VERSION 5.8 ;
DIVIDERCHAR "/" ;
BUSBITCHARS "[]" ;

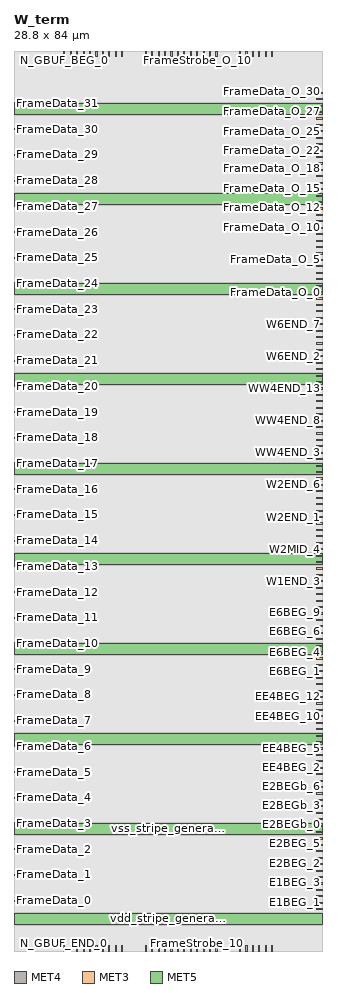
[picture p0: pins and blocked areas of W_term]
MACRO W_term
  CLASS BLOCK ;
  FOREIGN W_term ;
  ORIGIN 0.0 0.0 ;
  SIZE 28.800 BY 84.000 ;
  SYMMETRY X Y ;
  PIN S_GBUF_FEED_END_0
    DIRECTION INPUT ;
    USE SIGNAL ;
    PORT
      LAYER MET4 ;
        RECT 7.050 83.450 7.150 84.000 ;
    END
  END S_GBUF_FEED_END_0
  PIN S_GBUF_FEED_END_1
    DIRECTION INPUT ;
    USE SIGNAL ;
    PORT
      LAYER MET4 ;
        RECT 7.650 83.450 7.750 84.000 ;
    END
  END S_GBUF_FEED_END_1
  PIN S_GBUF_FEED_END_2
    DIRECTION INPUT ;
    USE SIGNAL ;
    PORT
      LAYER MET4 ;
        RECT 8.250 83.450 8.350 84.000 ;
    END
  END S_GBUF_FEED_END_2
  PIN S_GBUF_FEED_END_3
    DIRECTION INPUT ;
    USE SIGNAL ;
    PORT
      LAYER MET4 ;
        RECT 8.850 83.450 8.950 84.000 ;
    END
  END S_GBUF_FEED_END_3
  PIN N_GBUF_BEG_0
    DIRECTION OUTPUT ;
    USE SIGNAL ;
    PORT
      LAYER MET4 ;
        RECT 4.650 83.450 4.750 84.000 ;
    END
  END N_GBUF_BEG_0
  PIN N_GBUF_BEG_1
    DIRECTION OUTPUT ;
    USE SIGNAL ;
    PORT
      LAYER MET4 ;
        RECT 5.250 83.450 5.350 84.000 ;
    END
  END N_GBUF_BEG_1
  PIN N_GBUF_BEG_2
    DIRECTION OUTPUT ;
    USE SIGNAL ;
    PORT
      LAYER MET4 ;
        RECT 5.850 83.450 5.950 84.000 ;
    END
  END N_GBUF_BEG_2
  PIN N_GBUF_BEG_3
    DIRECTION OUTPUT ;
    USE SIGNAL ;
    PORT
      LAYER MET4 ;
        RECT 6.450 83.450 6.550 84.000 ;
    END
  END N_GBUF_BEG_3
  PIN E1BEG_0
    DIRECTION OUTPUT ;
    USE SIGNAL ;
    PORT
      LAYER MET3 ;
        RECT 28.250 3.850 28.800 3.950 ;
    END
  END E1BEG_0
  PIN E1BEG_1
    DIRECTION OUTPUT ;
    USE SIGNAL ;
    PORT
      LAYER MET3 ;
        RECT 28.250 4.450 28.800 4.550 ;
    END
  END E1BEG_1
  PIN E1BEG_2
    DIRECTION OUTPUT ;
    USE SIGNAL ;
    PORT
      LAYER MET3 ;
        RECT 28.250 5.050 28.800 5.150 ;
    END
  END E1BEG_2
  PIN E1BEG_3
    DIRECTION OUTPUT ;
    USE SIGNAL ;
    PORT
      LAYER MET3 ;
        RECT 28.250 5.650 28.800 5.750 ;
    END
  END E1BEG_3
  PIN E2BEG_0
    DIRECTION OUTPUT ;
    USE SIGNAL ;
    PORT
      LAYER MET3 ;
        RECT 28.250 6.250 28.800 6.350 ;
    END
  END E2BEG_0
  PIN E2BEG_1
    DIRECTION OUTPUT ;
    USE SIGNAL ;
    PORT
      LAYER MET3 ;
        RECT 28.250 6.850 28.800 6.950 ;
    END
  END E2BEG_1
  PIN E2BEG_2
    DIRECTION OUTPUT ;
    USE SIGNAL ;
    PORT
      LAYER MET3 ;
        RECT 28.250 7.450 28.800 7.550 ;
    END
  END E2BEG_2
  PIN E2BEG_3
    DIRECTION OUTPUT ;
    USE SIGNAL ;
    PORT
      LAYER MET3 ;
        RECT 28.250 8.050 28.800 8.150 ;
    END
  END E2BEG_3
  PIN E2BEG_4
    DIRECTION OUTPUT ;
    USE SIGNAL ;
    PORT
      LAYER MET3 ;
        RECT 28.250 8.650 28.800 8.750 ;
    END
  END E2BEG_4
  PIN E2BEG_5
    DIRECTION OUTPUT ;
    USE SIGNAL ;
    PORT
      LAYER MET3 ;
        RECT 28.250 9.250 28.800 9.350 ;
    END
  END E2BEG_5
  PIN E2BEG_6
    DIRECTION OUTPUT ;
    USE SIGNAL ;
    PORT
      LAYER MET3 ;
        RECT 28.250 9.850 28.800 9.950 ;
    END
  END E2BEG_6
  PIN E2BEG_7
    DIRECTION OUTPUT ;
    USE SIGNAL ;
    PORT
      LAYER MET3 ;
        RECT 28.250 10.450 28.800 10.550 ;
    END
  END E2BEG_7
  PIN E2BEGb_0
    DIRECTION OUTPUT ;
    USE SIGNAL ;
    PORT
      LAYER MET3 ;
        RECT 28.250 11.050 28.800 11.150 ;
    END
  END E2BEGb_0
  PIN E2BEGb_1
    DIRECTION OUTPUT ;
    USE SIGNAL ;
    PORT
      LAYER MET3 ;
        RECT 28.250 11.650 28.800 11.750 ;
    END
  END E2BEGb_1
  PIN E2BEGb_2
    DIRECTION OUTPUT ;
    USE SIGNAL ;
    PORT
      LAYER MET3 ;
        RECT 28.250 12.250 28.800 12.350 ;
    END
  END E2BEGb_2
  PIN E2BEGb_3
    DIRECTION OUTPUT ;
    USE SIGNAL ;
    PORT
      LAYER MET3 ;
        RECT 28.250 12.850 28.800 12.950 ;
    END
  END E2BEGb_3
  PIN E2BEGb_4
    DIRECTION OUTPUT ;
    USE SIGNAL ;
    PORT
      LAYER MET3 ;
        RECT 28.250 13.450 28.800 13.550 ;
    END
  END E2BEGb_4
  PIN E2BEGb_5
    DIRECTION OUTPUT ;
    USE SIGNAL ;
    PORT
      LAYER MET3 ;
        RECT 28.250 14.050 28.800 14.150 ;
    END
  END E2BEGb_5
  PIN E2BEGb_6
    DIRECTION OUTPUT ;
    USE SIGNAL ;
    PORT
      LAYER MET3 ;
        RECT 28.250 14.650 28.800 14.750 ;
    END
  END E2BEGb_6
  PIN E2BEGb_7
    DIRECTION OUTPUT ;
    USE SIGNAL ;
    PORT
      LAYER MET3 ;
        RECT 28.250 15.250 28.800 15.350 ;
    END
  END E2BEGb_7
  PIN EE4BEG_0
    DIRECTION OUTPUT ;
    USE SIGNAL ;
    PORT
      LAYER MET3 ;
        RECT 28.250 15.850 28.800 15.950 ;
    END
  END EE4BEG_0
  PIN EE4BEG_1
    DIRECTION OUTPUT ;
    USE SIGNAL ;
    PORT
      LAYER MET3 ;
        RECT 28.250 16.450 28.800 16.550 ;
    END
  END EE4BEG_1
  PIN EE4BEG_2
    DIRECTION OUTPUT ;
    USE SIGNAL ;
    PORT
      LAYER MET3 ;
        RECT 28.250 17.050 28.800 17.150 ;
    END
  END EE4BEG_2
  PIN EE4BEG_3
    DIRECTION OUTPUT ;
    USE SIGNAL ;
    PORT
      LAYER MET3 ;
        RECT 28.250 17.650 28.800 17.750 ;
    END
  END EE4BEG_3
  PIN EE4BEG_4
    DIRECTION OUTPUT ;
    USE SIGNAL ;
    PORT
      LAYER MET3 ;
        RECT 28.250 18.250 28.800 18.350 ;
    END
  END EE4BEG_4
  PIN EE4BEG_5
    DIRECTION OUTPUT ;
    USE SIGNAL ;
    PORT
      LAYER MET3 ;
        RECT 28.250 18.850 28.800 18.950 ;
    END
  END EE4BEG_5
  PIN EE4BEG_6
    DIRECTION OUTPUT ;
    USE SIGNAL ;
    PORT
      LAYER MET3 ;
        RECT 28.250 19.450 28.800 19.550 ;
    END
  END EE4BEG_6
  PIN EE4BEG_7
    DIRECTION OUTPUT ;
    USE SIGNAL ;
    PORT
      LAYER MET3 ;
        RECT 28.250 20.050 28.800 20.150 ;
    END
  END EE4BEG_7
  PIN EE4BEG_8
    DIRECTION OUTPUT ;
    USE SIGNAL ;
    PORT
      LAYER MET3 ;
        RECT 28.250 20.650 28.800 20.750 ;
    END
  END EE4BEG_8
  PIN EE4BEG_9
    DIRECTION OUTPUT ;
    USE SIGNAL ;
    PORT
      LAYER MET3 ;
        RECT 28.250 21.250 28.800 21.350 ;
    END
  END EE4BEG_9
  PIN EE4BEG_10
    DIRECTION OUTPUT ;
    USE SIGNAL ;
    PORT
      LAYER MET3 ;
        RECT 28.250 21.850 28.800 21.950 ;
    END
  END EE4BEG_10
  PIN EE4BEG_11
    DIRECTION OUTPUT ;
    USE SIGNAL ;
    PORT
      LAYER MET3 ;
        RECT 28.250 22.450 28.800 22.550 ;
    END
  END EE4BEG_11
  PIN EE4BEG_12
    DIRECTION OUTPUT ;
    USE SIGNAL ;
    PORT
      LAYER MET3 ;
        RECT 28.250 23.050 28.800 23.150 ;
    END
  END EE4BEG_12
  PIN EE4BEG_13
    DIRECTION OUTPUT ;
    USE SIGNAL ;
    PORT
      LAYER MET3 ;
        RECT 28.250 23.650 28.800 23.750 ;
    END
  END EE4BEG_13
  PIN EE4BEG_14
    DIRECTION OUTPUT ;
    USE SIGNAL ;
    PORT
      LAYER MET3 ;
        RECT 28.250 24.250 28.800 24.350 ;
    END
  END EE4BEG_14
  PIN EE4BEG_15
    DIRECTION OUTPUT ;
    USE SIGNAL ;
    PORT
      LAYER MET3 ;
        RECT 28.250 24.850 28.800 24.950 ;
    END
  END EE4BEG_15
  PIN E6BEG_0
    DIRECTION OUTPUT ;
    USE SIGNAL ;
    PORT
      LAYER MET3 ;
        RECT 28.250 25.450 28.800 25.550 ;
    END
  END E6BEG_0
  PIN E6BEG_1
    DIRECTION OUTPUT ;
    USE SIGNAL ;
    PORT
      LAYER MET3 ;
        RECT 28.250 26.050 28.800 26.150 ;
    END
  END E6BEG_1
  PIN E6BEG_2
    DIRECTION OUTPUT ;
    USE SIGNAL ;
    PORT
      LAYER MET3 ;
        RECT 28.250 26.650 28.800 26.750 ;
    END
  END E6BEG_2
  PIN E6BEG_3
    DIRECTION OUTPUT ;
    USE SIGNAL ;
    PORT
      LAYER MET3 ;
        RECT 28.250 27.250 28.800 27.350 ;
    END
  END E6BEG_3
  PIN E6BEG_4
    DIRECTION OUTPUT ;
    USE SIGNAL ;
    PORT
      LAYER MET3 ;
        RECT 28.250 27.850 28.800 27.950 ;
    END
  END E6BEG_4
  PIN E6BEG_5
    DIRECTION OUTPUT ;
    USE SIGNAL ;
    PORT
      LAYER MET3 ;
        RECT 28.250 28.450 28.800 28.550 ;
    END
  END E6BEG_5
  PIN E6BEG_6
    DIRECTION OUTPUT ;
    USE SIGNAL ;
    PORT
      LAYER MET3 ;
        RECT 28.250 29.050 28.800 29.150 ;
    END
  END E6BEG_6
  PIN E6BEG_7
    DIRECTION OUTPUT ;
    USE SIGNAL ;
    PORT
      LAYER MET3 ;
        RECT 28.250 29.650 28.800 29.750 ;
    END
  END E6BEG_7
  PIN E6BEG_8
    DIRECTION OUTPUT ;
    USE SIGNAL ;
    PORT
      LAYER MET3 ;
        RECT 28.250 30.250 28.800 30.350 ;
    END
  END E6BEG_8
  PIN E6BEG_9
    DIRECTION OUTPUT ;
    USE SIGNAL ;
    PORT
      LAYER MET3 ;
        RECT 28.250 30.850 28.800 30.950 ;
    END
  END E6BEG_9
  PIN E6BEG_10
    DIRECTION OUTPUT ;
    USE SIGNAL ;
    PORT
      LAYER MET3 ;
        RECT 28.250 31.450 28.800 31.550 ;
    END
  END E6BEG_10
  PIN E6BEG_11
    DIRECTION OUTPUT ;
    USE SIGNAL ;
    PORT
      LAYER MET3 ;
        RECT 28.250 32.050 28.800 32.150 ;
    END
  END E6BEG_11
  PIN W1END_0
    DIRECTION INPUT ;
    USE SIGNAL ;
    PORT
      LAYER MET3 ;
        RECT 28.250 32.650 28.800 32.750 ;
    END
  END W1END_0
  PIN W1END_1
    DIRECTION INPUT ;
    USE SIGNAL ;
    PORT
      LAYER MET3 ;
        RECT 28.250 33.250 28.800 33.350 ;
    END
  END W1END_1
  PIN W1END_2
    DIRECTION INPUT ;
    USE SIGNAL ;
    PORT
      LAYER MET3 ;
        RECT 28.250 33.850 28.800 33.950 ;
    END
  END W1END_2
  PIN W1END_3
    DIRECTION INPUT ;
    USE SIGNAL ;
    PORT
      LAYER MET3 ;
        RECT 28.250 34.450 28.800 34.550 ;
    END
  END W1END_3
  PIN W2MID_0
    DIRECTION INPUT ;
    USE SIGNAL ;
    PORT
      LAYER MET3 ;
        RECT 28.250 35.050 28.800 35.150 ;
    END
  END W2MID_0
  PIN W2MID_1
    DIRECTION INPUT ;
    USE SIGNAL ;
    PORT
      LAYER MET3 ;
        RECT 28.250 35.650 28.800 35.750 ;
    END
  END W2MID_1
  PIN W2MID_2
    DIRECTION INPUT ;
    USE SIGNAL ;
    PORT
      LAYER MET3 ;
        RECT 28.250 36.250 28.800 36.350 ;
    END
  END W2MID_2
  PIN W2MID_3
    DIRECTION INPUT ;
    USE SIGNAL ;
    PORT
      LAYER MET3 ;
        RECT 28.250 36.850 28.800 36.950 ;
    END
  END W2MID_3
  PIN W2MID_4
    DIRECTION INPUT ;
    USE SIGNAL ;
    PORT
      LAYER MET3 ;
        RECT 28.250 37.450 28.800 37.550 ;
    END
  END W2MID_4
  PIN W2MID_5
    DIRECTION INPUT ;
    USE SIGNAL ;
    PORT
      LAYER MET3 ;
        RECT 28.250 38.050 28.800 38.150 ;
    END
  END W2MID_5
  PIN W2MID_6
    DIRECTION INPUT ;
    USE SIGNAL ;
    PORT
      LAYER MET3 ;
        RECT 28.250 38.650 28.800 38.750 ;
    END
  END W2MID_6
  PIN W2MID_7
    DIRECTION INPUT ;
    USE SIGNAL ;
    PORT
      LAYER MET3 ;
        RECT 28.250 39.250 28.800 39.350 ;
    END
  END W2MID_7
  PIN W2END_0
    DIRECTION INPUT ;
    USE SIGNAL ;
    PORT
      LAYER MET3 ;
        RECT 28.250 39.850 28.800 39.950 ;
    END
  END W2END_0
  PIN W2END_1
    DIRECTION INPUT ;
    USE SIGNAL ;
    PORT
      LAYER MET3 ;
        RECT 28.250 40.450 28.800 40.550 ;
    END
  END W2END_1
  PIN W2END_2
    DIRECTION INPUT ;
    USE SIGNAL ;
    PORT
      LAYER MET3 ;
        RECT 28.250 41.050 28.800 41.150 ;
    END
  END W2END_2
  PIN W2END_3
    DIRECTION INPUT ;
    USE SIGNAL ;
    PORT
      LAYER MET3 ;
        RECT 28.250 41.650 28.800 41.750 ;
    END
  END W2END_3
  PIN W2END_4
    DIRECTION INPUT ;
    USE SIGNAL ;
    PORT
      LAYER MET3 ;
        RECT 28.250 42.250 28.800 42.350 ;
    END
  END W2END_4
  PIN W2END_5
    DIRECTION INPUT ;
    USE SIGNAL ;
    PORT
      LAYER MET3 ;
        RECT 28.250 42.850 28.800 42.950 ;
    END
  END W2END_5
  PIN W2END_6
    DIRECTION INPUT ;
    USE SIGNAL ;
    PORT
      LAYER MET3 ;
        RECT 28.250 43.450 28.800 43.550 ;
    END
  END W2END_6
  PIN W2END_7
    DIRECTION INPUT ;
    USE SIGNAL ;
    PORT
      LAYER MET3 ;
        RECT 28.250 44.050 28.800 44.150 ;
    END
  END W2END_7
  PIN WW4END_0
    DIRECTION INPUT ;
    USE SIGNAL ;
    PORT
      LAYER MET3 ;
        RECT 28.250 44.650 28.800 44.750 ;
    END
  END WW4END_0
  PIN WW4END_1
    DIRECTION INPUT ;
    USE SIGNAL ;
    PORT
      LAYER MET3 ;
        RECT 28.250 45.250 28.800 45.350 ;
    END
  END WW4END_1
  PIN WW4END_2
    DIRECTION INPUT ;
    USE SIGNAL ;
    PORT
      LAYER MET3 ;
        RECT 28.250 45.850 28.800 45.950 ;
    END
  END WW4END_2
  PIN WW4END_3
    DIRECTION INPUT ;
    USE SIGNAL ;
    PORT
      LAYER MET3 ;
        RECT 28.250 46.450 28.800 46.550 ;
    END
  END WW4END_3
  PIN WW4END_4
    DIRECTION INPUT ;
    USE SIGNAL ;
    PORT
      LAYER MET3 ;
        RECT 28.250 47.050 28.800 47.150 ;
    END
  END WW4END_4
  PIN WW4END_5
    DIRECTION INPUT ;
    USE SIGNAL ;
    PORT
      LAYER MET3 ;
        RECT 28.250 47.650 28.800 47.750 ;
    END
  END WW4END_5
  PIN WW4END_6
    DIRECTION INPUT ;
    USE SIGNAL ;
    PORT
      LAYER MET3 ;
        RECT 28.250 48.250 28.800 48.350 ;
    END
  END WW4END_6
  PIN WW4END_7
    DIRECTION INPUT ;
    USE SIGNAL ;
    PORT
      LAYER MET3 ;
        RECT 28.250 48.850 28.800 48.950 ;
    END
  END WW4END_7
  PIN WW4END_8
    DIRECTION INPUT ;
    USE SIGNAL ;
    PORT
      LAYER MET3 ;
        RECT 28.250 49.450 28.800 49.550 ;
    END
  END WW4END_8
  PIN WW4END_9
    DIRECTION INPUT ;
    USE SIGNAL ;
    PORT
      LAYER MET3 ;
        RECT 28.250 50.050 28.800 50.150 ;
    END
  END WW4END_9
  PIN WW4END_10
    DIRECTION INPUT ;
    USE SIGNAL ;
    PORT
      LAYER MET3 ;
        RECT 28.250 50.650 28.800 50.750 ;
    END
  END WW4END_10
  PIN WW4END_11
    DIRECTION INPUT ;
    USE SIGNAL ;
    PORT
      LAYER MET3 ;
        RECT 28.250 51.250 28.800 51.350 ;
    END
  END WW4END_11
  PIN WW4END_12
    DIRECTION INPUT ;
    USE SIGNAL ;
    PORT
      LAYER MET3 ;
        RECT 28.250 51.850 28.800 51.950 ;
    END
  END WW4END_12
  PIN WW4END_13
    DIRECTION INPUT ;
    USE SIGNAL ;
    PORT
      LAYER MET3 ;
        RECT 28.250 52.450 28.800 52.550 ;
    END
  END WW4END_13
  PIN WW4END_14
    DIRECTION INPUT ;
    USE SIGNAL ;
    PORT
      LAYER MET3 ;
        RECT 28.250 53.050 28.800 53.150 ;
    END
  END WW4END_14
  PIN WW4END_15
    DIRECTION INPUT ;
    USE SIGNAL ;
    PORT
      LAYER MET3 ;
        RECT 28.250 53.650 28.800 53.750 ;
    END
  END WW4END_15
  PIN W6END_0
    DIRECTION INPUT ;
    USE SIGNAL ;
    PORT
      LAYER MET3 ;
        RECT 28.250 54.250 28.800 54.350 ;
    END
  END W6END_0
  PIN W6END_1
    DIRECTION INPUT ;
    USE SIGNAL ;
    PORT
      LAYER MET3 ;
        RECT 28.250 54.850 28.800 54.950 ;
    END
  END W6END_1
  PIN W6END_2
    DIRECTION INPUT ;
    USE SIGNAL ;
    PORT
      LAYER MET3 ;
        RECT 28.250 55.450 28.800 55.550 ;
    END
  END W6END_2
  PIN W6END_3
    DIRECTION INPUT ;
    USE SIGNAL ;
    PORT
      LAYER MET3 ;
        RECT 28.250 56.050 28.800 56.150 ;
    END
  END W6END_3
  PIN W6END_4
    DIRECTION INPUT ;
    USE SIGNAL ;
    PORT
      LAYER MET3 ;
        RECT 28.250 56.650 28.800 56.750 ;
    END
  END W6END_4
  PIN W6END_5
    DIRECTION INPUT ;
    USE SIGNAL ;
    PORT
      LAYER MET3 ;
        RECT 28.250 57.250 28.800 57.350 ;
    END
  END W6END_5
  PIN W6END_6
    DIRECTION INPUT ;
    USE SIGNAL ;
    PORT
      LAYER MET3 ;
        RECT 28.250 57.850 28.800 57.950 ;
    END
  END W6END_6
  PIN W6END_7
    DIRECTION INPUT ;
    USE SIGNAL ;
    PORT
      LAYER MET3 ;
        RECT 28.250 58.450 28.800 58.550 ;
    END
  END W6END_7
  PIN W6END_8
    DIRECTION INPUT ;
    USE SIGNAL ;
    PORT
      LAYER MET3 ;
        RECT 28.250 59.050 28.800 59.150 ;
    END
  END W6END_8
  PIN W6END_9
    DIRECTION INPUT ;
    USE SIGNAL ;
    PORT
      LAYER MET3 ;
        RECT 28.250 59.650 28.800 59.750 ;
    END
  END W6END_9
  PIN W6END_10
    DIRECTION INPUT ;
    USE SIGNAL ;
    PORT
      LAYER MET3 ;
        RECT 28.250 60.250 28.800 60.350 ;
    END
  END W6END_10
  PIN W6END_11
    DIRECTION INPUT ;
    USE SIGNAL ;
    PORT
      LAYER MET3 ;
        RECT 28.250 60.850 28.800 60.950 ;
    END
  END W6END_11
  PIN S_GBUF_FEED_BEG_0
    DIRECTION OUTPUT ;
    USE SIGNAL ;
    PORT
      LAYER MET4 ;
        RECT 7.050 0.000 7.150 0.550 ;
    END
  END S_GBUF_FEED_BEG_0
  PIN S_GBUF_FEED_BEG_1
    DIRECTION OUTPUT ;
    USE SIGNAL ;
    PORT
      LAYER MET4 ;
        RECT 7.650 0.000 7.750 0.550 ;
    END
  END S_GBUF_FEED_BEG_1
  PIN S_GBUF_FEED_BEG_2
    DIRECTION OUTPUT ;
    USE SIGNAL ;
    PORT
      LAYER MET4 ;
        RECT 8.250 0.000 8.350 0.550 ;
    END
  END S_GBUF_FEED_BEG_2
  PIN S_GBUF_FEED_BEG_3
    DIRECTION OUTPUT ;
    USE SIGNAL ;
    PORT
      LAYER MET4 ;
        RECT 8.850 0.000 8.950 0.550 ;
    END
  END S_GBUF_FEED_BEG_3
  PIN N_GBUF_END_0
    DIRECTION INPUT ;
    USE SIGNAL ;
    PORT
      LAYER MET4 ;
        RECT 4.650 0.000 4.750 0.550 ;
    END
  END N_GBUF_END_0
  PIN N_GBUF_END_1
    DIRECTION INPUT ;
    USE SIGNAL ;
    PORT
      LAYER MET4 ;
        RECT 5.250 0.000 5.350 0.550 ;
    END
  END N_GBUF_END_1
  PIN N_GBUF_END_2
    DIRECTION INPUT ;
    USE SIGNAL ;
    PORT
      LAYER MET4 ;
        RECT 5.850 0.000 5.950 0.550 ;
    END
  END N_GBUF_END_2
  PIN N_GBUF_END_3
    DIRECTION INPUT ;
    USE SIGNAL ;
    PORT
      LAYER MET4 ;
        RECT 6.450 0.000 6.550 0.550 ;
    END
  END N_GBUF_END_3
  PIN FrameData_0
    DIRECTION INPUT ;
    USE SIGNAL ;
    PORT
      LAYER MET3 ;
        RECT 0.000 4.650 0.550 4.750 ;
    END
  END FrameData_0
  PIN FrameData_1
    DIRECTION INPUT ;
    USE SIGNAL ;
    PORT
      LAYER MET3 ;
        RECT 0.000 7.050 0.550 7.150 ;
    END
  END FrameData_1
  PIN FrameData_2
    DIRECTION INPUT ;
    USE SIGNAL ;
    PORT
      LAYER MET3 ;
        RECT 0.000 9.450 0.550 9.550 ;
    END
  END FrameData_2
  PIN FrameData_3
    DIRECTION INPUT ;
    USE SIGNAL ;
    PORT
      LAYER MET3 ;
        RECT 0.000 11.850 0.550 11.950 ;
    END
  END FrameData_3
  PIN FrameData_4
    DIRECTION INPUT ;
    USE SIGNAL ;
    PORT
      LAYER MET3 ;
        RECT 0.000 14.250 0.550 14.350 ;
    END
  END FrameData_4
  PIN FrameData_5
    DIRECTION INPUT ;
    USE SIGNAL ;
    PORT
      LAYER MET3 ;
        RECT 0.000 16.650 0.550 16.750 ;
    END
  END FrameData_5
  PIN FrameData_6
    DIRECTION INPUT ;
    USE SIGNAL ;
    PORT
      LAYER MET3 ;
        RECT 0.000 19.050 0.550 19.150 ;
    END
  END FrameData_6
  PIN FrameData_7
    DIRECTION INPUT ;
    USE SIGNAL ;
    PORT
      LAYER MET3 ;
        RECT 0.000 21.450 0.550 21.550 ;
    END
  END FrameData_7
  PIN FrameData_8
    DIRECTION INPUT ;
    USE SIGNAL ;
    PORT
      LAYER MET3 ;
        RECT 0.000 23.850 0.550 23.950 ;
    END
  END FrameData_8
  PIN FrameData_9
    DIRECTION INPUT ;
    USE SIGNAL ;
    PORT
      LAYER MET3 ;
        RECT 0.000 26.250 0.550 26.350 ;
    END
  END FrameData_9
  PIN FrameData_10
    DIRECTION INPUT ;
    USE SIGNAL ;
    PORT
      LAYER MET3 ;
        RECT 0.000 28.650 0.550 28.750 ;
    END
  END FrameData_10
  PIN FrameData_11
    DIRECTION INPUT ;
    USE SIGNAL ;
    PORT
      LAYER MET3 ;
        RECT 0.000 31.050 0.550 31.150 ;
    END
  END FrameData_11
  PIN FrameData_12
    DIRECTION INPUT ;
    USE SIGNAL ;
    PORT
      LAYER MET3 ;
        RECT 0.000 33.450 0.550 33.550 ;
    END
  END FrameData_12
  PIN FrameData_13
    DIRECTION INPUT ;
    USE SIGNAL ;
    PORT
      LAYER MET3 ;
        RECT 0.000 35.850 0.550 35.950 ;
    END
  END FrameData_13
  PIN FrameData_14
    DIRECTION INPUT ;
    USE SIGNAL ;
    PORT
      LAYER MET3 ;
        RECT 0.000 38.250 0.550 38.350 ;
    END
  END FrameData_14
  PIN FrameData_15
    DIRECTION INPUT ;
    USE SIGNAL ;
    PORT
      LAYER MET3 ;
        RECT 0.000 40.650 0.550 40.750 ;
    END
  END FrameData_15
  PIN FrameData_16
    DIRECTION INPUT ;
    USE SIGNAL ;
    PORT
      LAYER MET3 ;
        RECT 0.000 43.050 0.550 43.150 ;
    END
  END FrameData_16
  PIN FrameData_17
    DIRECTION INPUT ;
    USE SIGNAL ;
    PORT
      LAYER MET3 ;
        RECT 0.000 45.450 0.550 45.550 ;
    END
  END FrameData_17
  PIN FrameData_18
    DIRECTION INPUT ;
    USE SIGNAL ;
    PORT
      LAYER MET3 ;
        RECT 0.000 47.850 0.550 47.950 ;
    END
  END FrameData_18
  PIN FrameData_19
    DIRECTION INPUT ;
    USE SIGNAL ;
    PORT
      LAYER MET3 ;
        RECT 0.000 50.250 0.550 50.350 ;
    END
  END FrameData_19
  PIN FrameData_20
    DIRECTION INPUT ;
    USE SIGNAL ;
    PORT
      LAYER MET3 ;
        RECT 0.000 52.650 0.550 52.750 ;
    END
  END FrameData_20
  PIN FrameData_21
    DIRECTION INPUT ;
    USE SIGNAL ;
    PORT
      LAYER MET3 ;
        RECT 0.000 55.050 0.550 55.150 ;
    END
  END FrameData_21
  PIN FrameData_22
    DIRECTION INPUT ;
    USE SIGNAL ;
    PORT
      LAYER MET3 ;
        RECT 0.000 57.450 0.550 57.550 ;
    END
  END FrameData_22
  PIN FrameData_23
    DIRECTION INPUT ;
    USE SIGNAL ;
    PORT
      LAYER MET3 ;
        RECT 0.000 59.850 0.550 59.950 ;
    END
  END FrameData_23
  PIN FrameData_24
    DIRECTION INPUT ;
    USE SIGNAL ;
    PORT
      LAYER MET3 ;
        RECT 0.000 62.250 0.550 62.350 ;
    END
  END FrameData_24
  PIN FrameData_25
    DIRECTION INPUT ;
    USE SIGNAL ;
    PORT
      LAYER MET3 ;
        RECT 0.000 64.650 0.550 64.750 ;
    END
  END FrameData_25
  PIN FrameData_26
    DIRECTION INPUT ;
    USE SIGNAL ;
    PORT
      LAYER MET3 ;
        RECT 0.000 67.050 0.550 67.150 ;
    END
  END FrameData_26
  PIN FrameData_27
    DIRECTION INPUT ;
    USE SIGNAL ;
    PORT
      LAYER MET3 ;
        RECT 0.000 69.450 0.550 69.550 ;
    END
  END FrameData_27
  PIN FrameData_28
    DIRECTION INPUT ;
    USE SIGNAL ;
    PORT
      LAYER MET3 ;
        RECT 0.000 71.850 0.550 71.950 ;
    END
  END FrameData_28
  PIN FrameData_29
    DIRECTION INPUT ;
    USE SIGNAL ;
    PORT
      LAYER MET3 ;
        RECT 0.000 74.250 0.550 74.350 ;
    END
  END FrameData_29
  PIN FrameData_30
    DIRECTION INPUT ;
    USE SIGNAL ;
    PORT
      LAYER MET3 ;
        RECT 0.000 76.650 0.550 76.750 ;
    END
  END FrameData_30
  PIN FrameData_31
    DIRECTION INPUT ;
    USE SIGNAL ;
    PORT
      LAYER MET3 ;
        RECT 0.000 79.050 0.550 79.150 ;
    END
  END FrameData_31
  PIN FrameData_O_0
    DIRECTION OUTPUT ;
    USE SIGNAL ;
    PORT
      LAYER MET3 ;
        RECT 28.250 61.450 28.800 61.550 ;
    END
  END FrameData_O_0
  PIN FrameData_O_1
    DIRECTION OUTPUT ;
    USE SIGNAL ;
    PORT
      LAYER MET3 ;
        RECT 28.250 62.050 28.800 62.150 ;
    END
  END FrameData_O_1
  PIN FrameData_O_2
    DIRECTION OUTPUT ;
    USE SIGNAL ;
    PORT
      LAYER MET3 ;
        RECT 28.250 62.650 28.800 62.750 ;
    END
  END FrameData_O_2
  PIN FrameData_O_3
    DIRECTION OUTPUT ;
    USE SIGNAL ;
    PORT
      LAYER MET3 ;
        RECT 28.250 63.250 28.800 63.350 ;
    END
  END FrameData_O_3
  PIN FrameData_O_4
    DIRECTION OUTPUT ;
    USE SIGNAL ;
    PORT
      LAYER MET3 ;
        RECT 28.250 63.850 28.800 63.950 ;
    END
  END FrameData_O_4
  PIN FrameData_O_5
    DIRECTION OUTPUT ;
    USE SIGNAL ;
    PORT
      LAYER MET3 ;
        RECT 28.250 64.450 28.800 64.550 ;
    END
  END FrameData_O_5
  PIN FrameData_O_6
    DIRECTION OUTPUT ;
    USE SIGNAL ;
    PORT
      LAYER MET3 ;
        RECT 28.250 65.050 28.800 65.150 ;
    END
  END FrameData_O_6
  PIN FrameData_O_7
    DIRECTION OUTPUT ;
    USE SIGNAL ;
    PORT
      LAYER MET3 ;
        RECT 28.250 65.650 28.800 65.750 ;
    END
  END FrameData_O_7
  PIN FrameData_O_8
    DIRECTION OUTPUT ;
    USE SIGNAL ;
    PORT
      LAYER MET3 ;
        RECT 28.250 66.250 28.800 66.350 ;
    END
  END FrameData_O_8
  PIN FrameData_O_9
    DIRECTION OUTPUT ;
    USE SIGNAL ;
    PORT
      LAYER MET3 ;
        RECT 28.250 66.850 28.800 66.950 ;
    END
  END FrameData_O_9
  PIN FrameData_O_10
    DIRECTION OUTPUT ;
    USE SIGNAL ;
    PORT
      LAYER MET3 ;
        RECT 28.250 67.450 28.800 67.550 ;
    END
  END FrameData_O_10
  PIN FrameData_O_11
    DIRECTION OUTPUT ;
    USE SIGNAL ;
    PORT
      LAYER MET3 ;
        RECT 28.250 68.050 28.800 68.150 ;
    END
  END FrameData_O_11
  PIN FrameData_O_12
    DIRECTION OUTPUT ;
    USE SIGNAL ;
    PORT
      LAYER MET3 ;
        RECT 28.250 68.650 28.800 68.750 ;
    END
  END FrameData_O_12
  PIN FrameData_O_13
    DIRECTION OUTPUT ;
    USE SIGNAL ;
    PORT
      LAYER MET3 ;
        RECT 28.250 69.250 28.800 69.350 ;
    END
  END FrameData_O_13
  PIN FrameData_O_14
    DIRECTION OUTPUT ;
    USE SIGNAL ;
    PORT
      LAYER MET3 ;
        RECT 28.250 69.850 28.800 69.950 ;
    END
  END FrameData_O_14
  PIN FrameData_O_15
    DIRECTION OUTPUT ;
    USE SIGNAL ;
    PORT
      LAYER MET3 ;
        RECT 28.250 70.450 28.800 70.550 ;
    END
  END FrameData_O_15
  PIN FrameData_O_16
    DIRECTION OUTPUT ;
    USE SIGNAL ;
    PORT
      LAYER MET3 ;
        RECT 28.250 71.050 28.800 71.150 ;
    END
  END FrameData_O_16
  PIN FrameData_O_17
    DIRECTION OUTPUT ;
    USE SIGNAL ;
    PORT
      LAYER MET3 ;
        RECT 28.250 71.650 28.800 71.750 ;
    END
  END FrameData_O_17
  PIN FrameData_O_18
    DIRECTION OUTPUT ;
    USE SIGNAL ;
    PORT
      LAYER MET3 ;
        RECT 28.250 72.250 28.800 72.350 ;
    END
  END FrameData_O_18
  PIN FrameData_O_19
    DIRECTION OUTPUT ;
    USE SIGNAL ;
    PORT
      LAYER MET3 ;
        RECT 28.250 72.850 28.800 72.950 ;
    END
  END FrameData_O_19
  PIN FrameData_O_20
    DIRECTION OUTPUT ;
    USE SIGNAL ;
    PORT
      LAYER MET3 ;
        RECT 28.250 73.450 28.800 73.550 ;
    END
  END FrameData_O_20
  PIN FrameData_O_21
    DIRECTION OUTPUT ;
    USE SIGNAL ;
    PORT
      LAYER MET3 ;
        RECT 28.250 74.050 28.800 74.150 ;
    END
  END FrameData_O_21
  PIN FrameData_O_22
    DIRECTION OUTPUT ;
    USE SIGNAL ;
    PORT
      LAYER MET3 ;
        RECT 28.250 74.650 28.800 74.750 ;
    END
  END FrameData_O_22
  PIN FrameData_O_23
    DIRECTION OUTPUT ;
    USE SIGNAL ;
    PORT
      LAYER MET3 ;
        RECT 28.250 75.250 28.800 75.350 ;
    END
  END FrameData_O_23
  PIN FrameData_O_24
    DIRECTION OUTPUT ;
    USE SIGNAL ;
    PORT
      LAYER MET3 ;
        RECT 28.250 75.850 28.800 75.950 ;
    END
  END FrameData_O_24
  PIN FrameData_O_25
    DIRECTION OUTPUT ;
    USE SIGNAL ;
    PORT
      LAYER MET3 ;
        RECT 28.250 76.450 28.800 76.550 ;
    END
  END FrameData_O_25
  PIN FrameData_O_26
    DIRECTION OUTPUT ;
    USE SIGNAL ;
    PORT
      LAYER MET3 ;
        RECT 28.250 77.050 28.800 77.150 ;
    END
  END FrameData_O_26
  PIN FrameData_O_27
    DIRECTION OUTPUT ;
    USE SIGNAL ;
    PORT
      LAYER MET3 ;
        RECT 28.250 77.650 28.800 77.750 ;
    END
  END FrameData_O_27
  PIN FrameData_O_28
    DIRECTION OUTPUT ;
    USE SIGNAL ;
    PORT
      LAYER MET3 ;
        RECT 28.250 78.250 28.800 78.350 ;
    END
  END FrameData_O_28
  PIN FrameData_O_29
    DIRECTION OUTPUT ;
    USE SIGNAL ;
    PORT
      LAYER MET3 ;
        RECT 28.250 78.850 28.800 78.950 ;
    END
  END FrameData_O_29
  PIN FrameData_O_30
    DIRECTION OUTPUT ;
    USE SIGNAL ;
    PORT
      LAYER MET3 ;
        RECT 28.250 79.450 28.800 79.550 ;
    END
  END FrameData_O_30
  PIN FrameData_O_31
    DIRECTION OUTPUT ;
    USE SIGNAL ;
    PORT
      LAYER MET3 ;
        RECT 28.250 80.050 28.800 80.150 ;
    END
  END FrameData_O_31
  PIN FrameStrobe_0
    DIRECTION INPUT ;
    USE SIGNAL ;
    PORT
      LAYER MET4 ;
        RECT 9.450 0.000 9.550 0.550 ;
    END
  END FrameStrobe_0
  PIN FrameStrobe_1
    DIRECTION INPUT ;
    USE SIGNAL ;
    PORT
      LAYER MET4 ;
        RECT 10.050 0.000 10.150 0.550 ;
    END
  END FrameStrobe_1
  PIN FrameStrobe_2
    DIRECTION INPUT ;
    USE SIGNAL ;
    PORT
      LAYER MET4 ;
        RECT 12.250 0.000 12.350 0.550 ;
    END
  END FrameStrobe_2
  PIN FrameStrobe_3
    DIRECTION INPUT ;
    USE SIGNAL ;
    PORT
      LAYER MET4 ;
        RECT 12.850 0.000 12.950 0.550 ;
    END
  END FrameStrobe_3
  PIN FrameStrobe_4
    DIRECTION INPUT ;
    USE SIGNAL ;
    PORT
      LAYER MET4 ;
        RECT 13.450 0.000 13.550 0.550 ;
    END
  END FrameStrobe_4
  PIN FrameStrobe_5
    DIRECTION INPUT ;
    USE SIGNAL ;
    PORT
      LAYER MET4 ;
        RECT 14.050 0.000 14.150 0.550 ;
    END
  END FrameStrobe_5
  PIN FrameStrobe_6
    DIRECTION INPUT ;
    USE SIGNAL ;
    PORT
      LAYER MET4 ;
        RECT 14.650 0.000 14.750 0.550 ;
    END
  END FrameStrobe_6
  PIN FrameStrobe_7
    DIRECTION INPUT ;
    USE SIGNAL ;
    PORT
      LAYER MET4 ;
        RECT 15.250 0.000 15.350 0.550 ;
    END
  END FrameStrobe_7
  PIN FrameStrobe_8
    DIRECTION INPUT ;
    USE SIGNAL ;
    PORT
      LAYER MET4 ;
        RECT 15.850 0.000 15.950 0.550 ;
    END
  END FrameStrobe_8
  PIN FrameStrobe_9
    DIRECTION INPUT ;
    USE SIGNAL ;
    PORT
      LAYER MET4 ;
        RECT 16.450 0.000 16.550 0.550 ;
    END
  END FrameStrobe_9
  PIN FrameStrobe_10
    DIRECTION INPUT ;
    USE SIGNAL ;
    PORT
      LAYER MET4 ;
        RECT 17.050 0.000 17.150 0.550 ;
    END
  END FrameStrobe_10
  PIN FrameStrobe_11
    DIRECTION INPUT ;
    USE SIGNAL ;
    PORT
      LAYER MET4 ;
        RECT 17.650 0.000 17.750 0.550 ;
    END
  END FrameStrobe_11
  PIN FrameStrobe_12
    DIRECTION INPUT ;
    USE SIGNAL ;
    PORT
      LAYER MET4 ;
        RECT 18.250 0.000 18.350 0.550 ;
    END
  END FrameStrobe_12
  PIN FrameStrobe_13
    DIRECTION INPUT ;
    USE SIGNAL ;
    PORT
      LAYER MET4 ;
        RECT 18.850 0.000 18.950 0.550 ;
    END
  END FrameStrobe_13
  PIN FrameStrobe_14
    DIRECTION INPUT ;
    USE SIGNAL ;
    PORT
      LAYER MET4 ;
        RECT 21.050 0.000 21.150 0.550 ;
    END
  END FrameStrobe_14
  PIN FrameStrobe_15
    DIRECTION INPUT ;
    USE SIGNAL ;
    PORT
      LAYER MET4 ;
        RECT 21.650 0.000 21.750 0.550 ;
    END
  END FrameStrobe_15
  PIN FrameStrobe_16
    DIRECTION INPUT ;
    USE SIGNAL ;
    PORT
      LAYER MET4 ;
        RECT 22.250 0.000 22.350 0.550 ;
    END
  END FrameStrobe_16
  PIN FrameStrobe_17
    DIRECTION INPUT ;
    USE SIGNAL ;
    PORT
      LAYER MET4 ;
        RECT 22.850 0.000 22.950 0.550 ;
    END
  END FrameStrobe_17
  PIN FrameStrobe_18
    DIRECTION INPUT ;
    USE SIGNAL ;
    PORT
      LAYER MET4 ;
        RECT 23.450 0.000 23.550 0.550 ;
    END
  END FrameStrobe_18
  PIN FrameStrobe_19
    DIRECTION INPUT ;
    USE SIGNAL ;
    PORT
      LAYER MET4 ;
        RECT 24.050 0.000 24.150 0.550 ;
    END
  END FrameStrobe_19
  PIN FrameStrobe_O_0
    DIRECTION OUTPUT ;
    USE SIGNAL ;
    PORT
      LAYER MET4 ;
        RECT 9.450 83.450 9.550 84.000 ;
    END
  END FrameStrobe_O_0
  PIN FrameStrobe_O_1
    DIRECTION OUTPUT ;
    USE SIGNAL ;
    PORT
      LAYER MET4 ;
        RECT 10.050 83.450 10.150 84.000 ;
    END
  END FrameStrobe_O_1
  PIN FrameStrobe_O_2
    DIRECTION OUTPUT ;
    USE SIGNAL ;
    PORT
      LAYER MET4 ;
        RECT 12.250 83.450 12.350 84.000 ;
    END
  END FrameStrobe_O_2
  PIN FrameStrobe_O_3
    DIRECTION OUTPUT ;
    USE SIGNAL ;
    PORT
      LAYER MET4 ;
        RECT 12.850 83.450 12.950 84.000 ;
    END
  END FrameStrobe_O_3
  PIN FrameStrobe_O_4
    DIRECTION OUTPUT ;
    USE SIGNAL ;
    PORT
      LAYER MET4 ;
        RECT 13.450 83.450 13.550 84.000 ;
    END
  END FrameStrobe_O_4
  PIN FrameStrobe_O_5
    DIRECTION OUTPUT ;
    USE SIGNAL ;
    PORT
      LAYER MET4 ;
        RECT 14.050 83.450 14.150 84.000 ;
    END
  END FrameStrobe_O_5
  PIN FrameStrobe_O_6
    DIRECTION OUTPUT ;
    USE SIGNAL ;
    PORT
      LAYER MET4 ;
        RECT 14.650 83.450 14.750 84.000 ;
    END
  END FrameStrobe_O_6
  PIN FrameStrobe_O_7
    DIRECTION OUTPUT ;
    USE SIGNAL ;
    PORT
      LAYER MET4 ;
        RECT 15.250 83.450 15.350 84.000 ;
    END
  END FrameStrobe_O_7
  PIN FrameStrobe_O_8
    DIRECTION OUTPUT ;
    USE SIGNAL ;
    PORT
      LAYER MET4 ;
        RECT 15.850 83.450 15.950 84.000 ;
    END
  END FrameStrobe_O_8
  PIN FrameStrobe_O_9
    DIRECTION OUTPUT ;
    USE SIGNAL ;
    PORT
      LAYER MET4 ;
        RECT 16.450 83.450 16.550 84.000 ;
    END
  END FrameStrobe_O_9
  PIN FrameStrobe_O_10
    DIRECTION OUTPUT ;
    USE SIGNAL ;
    PORT
      LAYER MET4 ;
        RECT 17.050 83.450 17.150 84.000 ;
    END
  END FrameStrobe_O_10
  PIN FrameStrobe_O_11
    DIRECTION OUTPUT ;
    USE SIGNAL ;
    PORT
      LAYER MET4 ;
        RECT 17.650 83.450 17.750 84.000 ;
    END
  END FrameStrobe_O_11
  PIN FrameStrobe_O_12
    DIRECTION OUTPUT ;
    USE SIGNAL ;
    PORT
      LAYER MET4 ;
        RECT 18.250 83.450 18.350 84.000 ;
    END
  END FrameStrobe_O_12
  PIN FrameStrobe_O_13
    DIRECTION OUTPUT ;
    USE SIGNAL ;
    PORT
      LAYER MET4 ;
        RECT 18.850 83.450 18.950 84.000 ;
    END
  END FrameStrobe_O_13
  PIN FrameStrobe_O_14
    DIRECTION OUTPUT ;
    USE SIGNAL ;
    PORT
      LAYER MET4 ;
        RECT 21.050 83.450 21.150 84.000 ;
    END
  END FrameStrobe_O_14
  PIN FrameStrobe_O_15
    DIRECTION OUTPUT ;
    USE SIGNAL ;
    PORT
      LAYER MET4 ;
        RECT 21.650 83.450 21.750 84.000 ;
    END
  END FrameStrobe_O_15
  PIN FrameStrobe_O_16
    DIRECTION OUTPUT ;
    USE SIGNAL ;
    PORT
      LAYER MET4 ;
        RECT 22.250 83.450 22.350 84.000 ;
    END
  END FrameStrobe_O_16
  PIN FrameStrobe_O_17
    DIRECTION OUTPUT ;
    USE SIGNAL ;
    PORT
      LAYER MET4 ;
        RECT 22.850 83.450 22.950 84.000 ;
    END
  END FrameStrobe_O_17
  PIN FrameStrobe_O_18
    DIRECTION OUTPUT ;
    USE SIGNAL ;
    PORT
      LAYER MET4 ;
        RECT 23.450 83.450 23.550 84.000 ;
    END
  END FrameStrobe_O_18
  PIN FrameStrobe_O_19
    DIRECTION OUTPUT ;
    USE SIGNAL ;
    PORT
      LAYER MET4 ;
        RECT 24.050 83.450 24.150 84.000 ;
    END
  END FrameStrobe_O_19
  PIN vdd_stripe_generate
    DIRECTION INOUT ;
    USE POWER ;
    PORT
      LAYER MET5 ;
        RECT 0.000 2.500 28.800 3.500 ;
      LAYER MET5 ;
        RECT 0.000 19.300 28.800 20.300 ;
      LAYER MET5 ;
        RECT 0.000 36.100 28.800 37.100 ;
      LAYER MET5 ;
        RECT 0.000 52.900 28.800 53.900 ;
      LAYER MET5 ;
        RECT 0.000 69.700 28.800 70.700 ;
    END
  END vdd_stripe_generate
  PIN vss_stripe_generate
    DIRECTION INOUT ;
    USE GROUND ;
    PORT
      LAYER MET5 ;
        RECT 0.000 10.900 28.800 11.900 ;
      LAYER MET5 ;
        RECT 0.000 27.700 28.800 28.700 ;
      LAYER MET5 ;
        RECT 0.000 44.500 28.800 45.500 ;
      LAYER MET5 ;
        RECT 0.000 61.300 28.800 62.300 ;
      LAYER MET5 ;
        RECT 0.000 78.100 28.800 79.100 ;
    END
  END vss_stripe_generate
  OBS
    LAYER MET1 ;
    RECT 0.000 0.000 28.800 84.000 ;
    LAYER MET2 ;
    RECT 0.000 0.000 28.800 84.000 ;
    LAYER MET3 ;
    RECT 0.000 0.000 28.800 3.750 ;
    LAYER MET3 ;
    RECT 0.000 3.750 28.150 4.050 ;
    LAYER MET3 ;
    RECT 0.000 4.050 28.800 4.350 ;
    LAYER MET3 ;
    RECT 0.000 4.350 28.150 4.550 ;
    LAYER MET3 ;
    RECT 0.650 4.550 28.150 4.650 ;
    LAYER MET3 ;
    RECT 0.650 4.650 28.800 4.850 ;
    LAYER MET3 ;
    RECT 0.000 4.850 28.800 4.950 ;
    LAYER MET3 ;
    RECT 0.000 4.950 28.150 5.250 ;
    LAYER MET3 ;
    RECT 0.000 5.250 28.800 5.550 ;
    LAYER MET3 ;
    RECT 0.000 5.550 28.150 5.850 ;
    LAYER MET3 ;
    RECT 0.000 5.850 28.800 6.150 ;
    LAYER MET3 ;
    RECT 0.000 6.150 28.150 6.450 ;
    LAYER MET3 ;
    RECT 0.000 6.450 28.800 6.750 ;
    LAYER MET3 ;
    RECT 0.000 6.750 28.150 6.950 ;
    LAYER MET3 ;
    RECT 0.650 6.950 28.150 7.050 ;
    LAYER MET3 ;
    RECT 0.650 7.050 28.800 7.250 ;
    LAYER MET3 ;
    RECT 0.000 7.250 28.800 7.350 ;
    LAYER MET3 ;
    RECT 0.000 7.350 28.150 7.650 ;
    LAYER MET3 ;
    RECT 0.000 7.650 28.800 7.950 ;
    LAYER MET3 ;
    RECT 0.000 7.950 28.150 8.250 ;
    LAYER MET3 ;
    RECT 0.000 8.250 28.800 8.550 ;
    LAYER MET3 ;
    RECT 0.000 8.550 28.150 8.850 ;
    LAYER MET3 ;
    RECT 0.000 8.850 28.800 9.150 ;
    LAYER MET3 ;
    RECT 0.000 9.150 28.150 9.350 ;
    LAYER MET3 ;
    RECT 0.650 9.350 28.150 9.450 ;
    LAYER MET3 ;
    RECT 0.650 9.450 28.800 9.650 ;
    LAYER MET3 ;
    RECT 0.000 9.650 28.800 9.750 ;
    LAYER MET3 ;
    RECT 0.000 9.750 28.150 10.050 ;
    LAYER MET3 ;
    RECT 0.000 10.050 28.800 10.350 ;
    LAYER MET3 ;
    RECT 0.000 10.350 28.150 10.650 ;
    LAYER MET3 ;
    RECT 0.000 10.650 28.800 10.950 ;
    LAYER MET3 ;
    RECT 0.000 10.950 28.150 11.250 ;
    LAYER MET3 ;
    RECT 0.000 11.250 28.800 11.550 ;
    LAYER MET3 ;
    RECT 0.000 11.550 28.150 11.750 ;
    LAYER MET3 ;
    RECT 0.650 11.750 28.150 11.850 ;
    LAYER MET3 ;
    RECT 0.650 11.850 28.800 12.050 ;
    LAYER MET3 ;
    RECT 0.000 12.050 28.800 12.150 ;
    LAYER MET3 ;
    RECT 0.000 12.150 28.150 12.450 ;
    LAYER MET3 ;
    RECT 0.000 12.450 28.800 12.750 ;
    LAYER MET3 ;
    RECT 0.000 12.750 28.150 13.050 ;
    LAYER MET3 ;
    RECT 0.000 13.050 28.800 13.350 ;
    LAYER MET3 ;
    RECT 0.000 13.350 28.150 13.650 ;
    LAYER MET3 ;
    RECT 0.000 13.650 28.800 13.950 ;
    LAYER MET3 ;
    RECT 0.000 13.950 28.150 14.150 ;
    LAYER MET3 ;
    RECT 0.650 14.150 28.150 14.250 ;
    LAYER MET3 ;
    RECT 0.650 14.250 28.800 14.450 ;
    LAYER MET3 ;
    RECT 0.000 14.450 28.800 14.550 ;
    LAYER MET3 ;
    RECT 0.000 14.550 28.150 14.850 ;
    LAYER MET3 ;
    RECT 0.000 14.850 28.800 15.150 ;
    LAYER MET3 ;
    RECT 0.000 15.150 28.150 15.450 ;
    LAYER MET3 ;
    RECT 0.000 15.450 28.800 15.750 ;
    LAYER MET3 ;
    RECT 0.000 15.750 28.150 16.050 ;
    LAYER MET3 ;
    RECT 0.000 16.050 28.800 16.350 ;
    LAYER MET3 ;
    RECT 0.000 16.350 28.150 16.550 ;
    LAYER MET3 ;
    RECT 0.650 16.550 28.150 16.650 ;
    LAYER MET3 ;
    RECT 0.650 16.650 28.800 16.850 ;
    LAYER MET3 ;
    RECT 0.000 16.850 28.800 16.950 ;
    LAYER MET3 ;
    RECT 0.000 16.950 28.150 17.250 ;
    LAYER MET3 ;
    RECT 0.000 17.250 28.800 17.550 ;
    LAYER MET3 ;
    RECT 0.000 17.550 28.150 17.850 ;
    LAYER MET3 ;
    RECT 0.000 17.850 28.800 18.150 ;
    LAYER MET3 ;
    RECT 0.000 18.150 28.150 18.450 ;
    LAYER MET3 ;
    RECT 0.000 18.450 28.800 18.750 ;
    LAYER MET3 ;
    RECT 0.000 18.750 28.150 18.950 ;
    LAYER MET3 ;
    RECT 0.650 18.950 28.150 19.050 ;
    LAYER MET3 ;
    RECT 0.650 19.050 28.800 19.250 ;
    LAYER MET3 ;
    RECT 0.000 19.250 28.800 19.350 ;
    LAYER MET3 ;
    RECT 0.000 19.350 28.150 19.650 ;
    LAYER MET3 ;
    RECT 0.000 19.650 28.800 19.950 ;
    LAYER MET3 ;
    RECT 0.000 19.950 28.150 20.250 ;
    LAYER MET3 ;
    RECT 0.000 20.250 28.800 20.550 ;
    LAYER MET3 ;
    RECT 0.000 20.550 28.150 20.850 ;
    LAYER MET3 ;
    RECT 0.000 20.850 28.800 21.150 ;
    LAYER MET3 ;
    RECT 0.000 21.150 28.150 21.350 ;
    LAYER MET3 ;
    RECT 0.650 21.350 28.150 21.450 ;
    LAYER MET3 ;
    RECT 0.650 21.450 28.800 21.650 ;
    LAYER MET3 ;
    RECT 0.000 21.650 28.800 21.750 ;
    LAYER MET3 ;
    RECT 0.000 21.750 28.150 22.050 ;
    LAYER MET3 ;
    RECT 0.000 22.050 28.800 22.350 ;
    LAYER MET3 ;
    RECT 0.000 22.350 28.150 22.650 ;
    LAYER MET3 ;
    RECT 0.000 22.650 28.800 22.950 ;
    LAYER MET3 ;
    RECT 0.000 22.950 28.150 23.250 ;
    LAYER MET3 ;
    RECT 0.000 23.250 28.800 23.550 ;
    LAYER MET3 ;
    RECT 0.000 23.550 28.150 23.750 ;
    LAYER MET3 ;
    RECT 0.650 23.750 28.150 23.850 ;
    LAYER MET3 ;
    RECT 0.650 23.850 28.800 24.050 ;
    LAYER MET3 ;
    RECT 0.000 24.050 28.800 24.150 ;
    LAYER MET3 ;
    RECT 0.000 24.150 28.150 24.450 ;
    LAYER MET3 ;
    RECT 0.000 24.450 28.800 24.750 ;
    LAYER MET3 ;
    RECT 0.000 24.750 28.150 25.050 ;
    LAYER MET3 ;
    RECT 0.000 25.050 28.800 25.350 ;
    LAYER MET3 ;
    RECT 0.000 25.350 28.150 25.650 ;
    LAYER MET3 ;
    RECT 0.000 25.650 28.800 25.950 ;
    LAYER MET3 ;
    RECT 0.000 25.950 28.150 26.150 ;
    LAYER MET3 ;
    RECT 0.650 26.150 28.150 26.250 ;
    LAYER MET3 ;
    RECT 0.650 26.250 28.800 26.450 ;
    LAYER MET3 ;
    RECT 0.000 26.450 28.800 26.550 ;
    LAYER MET3 ;
    RECT 0.000 26.550 28.150 26.850 ;
    LAYER MET3 ;
    RECT 0.000 26.850 28.800 27.150 ;
    LAYER MET3 ;
    RECT 0.000 27.150 28.150 27.450 ;
    LAYER MET3 ;
    RECT 0.000 27.450 28.800 27.750 ;
    LAYER MET3 ;
    RECT 0.000 27.750 28.150 28.050 ;
    LAYER MET3 ;
    RECT 0.000 28.050 28.800 28.350 ;
    LAYER MET3 ;
    RECT 0.000 28.350 28.150 28.550 ;
    LAYER MET3 ;
    RECT 0.650 28.550 28.150 28.650 ;
    LAYER MET3 ;
    RECT 0.650 28.650 28.800 28.850 ;
    LAYER MET3 ;
    RECT 0.000 28.850 28.800 28.950 ;
    LAYER MET3 ;
    RECT 0.000 28.950 28.150 29.250 ;
    LAYER MET3 ;
    RECT 0.000 29.250 28.800 29.550 ;
    LAYER MET3 ;
    RECT 0.000 29.550 28.150 29.850 ;
    LAYER MET3 ;
    RECT 0.000 29.850 28.800 30.150 ;
    LAYER MET3 ;
    RECT 0.000 30.150 28.150 30.450 ;
    LAYER MET3 ;
    RECT 0.000 30.450 28.800 30.750 ;
    LAYER MET3 ;
    RECT 0.000 30.750 28.150 30.950 ;
    LAYER MET3 ;
    RECT 0.650 30.950 28.150 31.050 ;
    LAYER MET3 ;
    RECT 0.650 31.050 28.800 31.250 ;
    LAYER MET3 ;
    RECT 0.000 31.250 28.800 31.350 ;
    LAYER MET3 ;
    RECT 0.000 31.350 28.150 31.650 ;
    LAYER MET3 ;
    RECT 0.000 31.650 28.800 31.950 ;
    LAYER MET3 ;
    RECT 0.000 31.950 28.150 32.250 ;
    LAYER MET3 ;
    RECT 0.000 32.250 28.800 32.550 ;
    LAYER MET3 ;
    RECT 0.000 32.550 28.150 32.850 ;
    LAYER MET3 ;
    RECT 0.000 32.850 28.800 33.150 ;
    LAYER MET3 ;
    RECT 0.000 33.150 28.150 33.350 ;
    LAYER MET3 ;
    RECT 0.650 33.350 28.150 33.450 ;
    LAYER MET3 ;
    RECT 0.650 33.450 28.800 33.650 ;
    LAYER MET3 ;
    RECT 0.000 33.650 28.800 33.750 ;
    LAYER MET3 ;
    RECT 0.000 33.750 28.150 34.050 ;
    LAYER MET3 ;
    RECT 0.000 34.050 28.800 34.350 ;
    LAYER MET3 ;
    RECT 0.000 34.350 28.150 34.650 ;
    LAYER MET3 ;
    RECT 0.000 34.650 28.800 34.950 ;
    LAYER MET3 ;
    RECT 0.000 34.950 28.150 35.250 ;
    LAYER MET3 ;
    RECT 0.000 35.250 28.800 35.550 ;
    LAYER MET3 ;
    RECT 0.000 35.550 28.150 35.750 ;
    LAYER MET3 ;
    RECT 0.650 35.750 28.150 35.850 ;
    LAYER MET3 ;
    RECT 0.650 35.850 28.800 36.050 ;
    LAYER MET3 ;
    RECT 0.000 36.050 28.800 36.150 ;
    LAYER MET3 ;
    RECT 0.000 36.150 28.150 36.450 ;
    LAYER MET3 ;
    RECT 0.000 36.450 28.800 36.750 ;
    LAYER MET3 ;
    RECT 0.000 36.750 28.150 37.050 ;
    LAYER MET3 ;
    RECT 0.000 37.050 28.800 37.350 ;
    LAYER MET3 ;
    RECT 0.000 37.350 28.150 37.650 ;
    LAYER MET3 ;
    RECT 0.000 37.650 28.800 37.950 ;
    LAYER MET3 ;
    RECT 0.000 37.950 28.150 38.150 ;
    LAYER MET3 ;
    RECT 0.650 38.150 28.150 38.250 ;
    LAYER MET3 ;
    RECT 0.650 38.250 28.800 38.450 ;
    LAYER MET3 ;
    RECT 0.000 38.450 28.800 38.550 ;
    LAYER MET3 ;
    RECT 0.000 38.550 28.150 38.850 ;
    LAYER MET3 ;
    RECT 0.000 38.850 28.800 39.150 ;
    LAYER MET3 ;
    RECT 0.000 39.150 28.150 39.450 ;
    LAYER MET3 ;
    RECT 0.000 39.450 28.800 39.750 ;
    LAYER MET3 ;
    RECT 0.000 39.750 28.150 40.050 ;
    LAYER MET3 ;
    RECT 0.000 40.050 28.800 40.350 ;
    LAYER MET3 ;
    RECT 0.000 40.350 28.150 40.550 ;
    LAYER MET3 ;
    RECT 0.650 40.550 28.150 40.650 ;
    LAYER MET3 ;
    RECT 0.650 40.650 28.800 40.850 ;
    LAYER MET3 ;
    RECT 0.000 40.850 28.800 40.950 ;
    LAYER MET3 ;
    RECT 0.000 40.950 28.150 41.250 ;
    LAYER MET3 ;
    RECT 0.000 41.250 28.800 41.550 ;
    LAYER MET3 ;
    RECT 0.000 41.550 28.150 41.850 ;
    LAYER MET3 ;
    RECT 0.000 41.850 28.800 42.150 ;
    LAYER MET3 ;
    RECT 0.000 42.150 28.150 42.450 ;
    LAYER MET3 ;
    RECT 0.000 42.450 28.800 42.750 ;
    LAYER MET3 ;
    RECT 0.000 42.750 28.150 42.950 ;
    LAYER MET3 ;
    RECT 0.650 42.950 28.150 43.050 ;
    LAYER MET3 ;
    RECT 0.650 43.050 28.800 43.250 ;
    LAYER MET3 ;
    RECT 0.000 43.250 28.800 43.350 ;
    LAYER MET3 ;
    RECT 0.000 43.350 28.150 43.650 ;
    LAYER MET3 ;
    RECT 0.000 43.650 28.800 43.950 ;
    LAYER MET3 ;
    RECT 0.000 43.950 28.150 44.250 ;
    LAYER MET3 ;
    RECT 0.000 44.250 28.800 44.550 ;
    LAYER MET3 ;
    RECT 0.000 44.550 28.150 44.850 ;
    LAYER MET3 ;
    RECT 0.000 44.850 28.800 45.150 ;
    LAYER MET3 ;
    RECT 0.000 45.150 28.150 45.350 ;
    LAYER MET3 ;
    RECT 0.650 45.350 28.150 45.450 ;
    LAYER MET3 ;
    RECT 0.650 45.450 28.800 45.650 ;
    LAYER MET3 ;
    RECT 0.000 45.650 28.800 45.750 ;
    LAYER MET3 ;
    RECT 0.000 45.750 28.150 46.050 ;
    LAYER MET3 ;
    RECT 0.000 46.050 28.800 46.350 ;
    LAYER MET3 ;
    RECT 0.000 46.350 28.150 46.650 ;
    LAYER MET3 ;
    RECT 0.000 46.650 28.800 46.950 ;
    LAYER MET3 ;
    RECT 0.000 46.950 28.150 47.250 ;
    LAYER MET3 ;
    RECT 0.000 47.250 28.800 47.550 ;
    LAYER MET3 ;
    RECT 0.000 47.550 28.150 47.750 ;
    LAYER MET3 ;
    RECT 0.650 47.750 28.150 47.850 ;
    LAYER MET3 ;
    RECT 0.650 47.850 28.800 48.050 ;
    LAYER MET3 ;
    RECT 0.000 48.050 28.800 48.150 ;
    LAYER MET3 ;
    RECT 0.000 48.150 28.150 48.450 ;
    LAYER MET3 ;
    RECT 0.000 48.450 28.800 48.750 ;
    LAYER MET3 ;
    RECT 0.000 48.750 28.150 49.050 ;
    LAYER MET3 ;
    RECT 0.000 49.050 28.800 49.350 ;
    LAYER MET3 ;
    RECT 0.000 49.350 28.150 49.650 ;
    LAYER MET3 ;
    RECT 0.000 49.650 28.800 49.950 ;
    LAYER MET3 ;
    RECT 0.000 49.950 28.150 50.150 ;
    LAYER MET3 ;
    RECT 0.650 50.150 28.150 50.250 ;
    LAYER MET3 ;
    RECT 0.650 50.250 28.800 50.450 ;
    LAYER MET3 ;
    RECT 0.000 50.450 28.800 50.550 ;
    LAYER MET3 ;
    RECT 0.000 50.550 28.150 50.850 ;
    LAYER MET3 ;
    RECT 0.000 50.850 28.800 51.150 ;
    LAYER MET3 ;
    RECT 0.000 51.150 28.150 51.450 ;
    LAYER MET3 ;
    RECT 0.000 51.450 28.800 51.750 ;
    LAYER MET3 ;
    RECT 0.000 51.750 28.150 52.050 ;
    LAYER MET3 ;
    RECT 0.000 52.050 28.800 52.350 ;
    LAYER MET3 ;
    RECT 0.000 52.350 28.150 52.550 ;
    LAYER MET3 ;
    RECT 0.650 52.550 28.150 52.650 ;
    LAYER MET3 ;
    RECT 0.650 52.650 28.800 52.850 ;
    LAYER MET3 ;
    RECT 0.000 52.850 28.800 52.950 ;
    LAYER MET3 ;
    RECT 0.000 52.950 28.150 53.250 ;
    LAYER MET3 ;
    RECT 0.000 53.250 28.800 53.550 ;
    LAYER MET3 ;
    RECT 0.000 53.550 28.150 53.850 ;
    LAYER MET3 ;
    RECT 0.000 53.850 28.800 54.150 ;
    LAYER MET3 ;
    RECT 0.000 54.150 28.150 54.450 ;
    LAYER MET3 ;
    RECT 0.000 54.450 28.800 54.750 ;
    LAYER MET3 ;
    RECT 0.000 54.750 28.150 54.950 ;
    LAYER MET3 ;
    RECT 0.650 54.950 28.150 55.050 ;
    LAYER MET3 ;
    RECT 0.650 55.050 28.800 55.250 ;
    LAYER MET3 ;
    RECT 0.000 55.250 28.800 55.350 ;
    LAYER MET3 ;
    RECT 0.000 55.350 28.150 55.650 ;
    LAYER MET3 ;
    RECT 0.000 55.650 28.800 55.950 ;
    LAYER MET3 ;
    RECT 0.000 55.950 28.150 56.250 ;
    LAYER MET3 ;
    RECT 0.000 56.250 28.800 56.550 ;
    LAYER MET3 ;
    RECT 0.000 56.550 28.150 56.850 ;
    LAYER MET3 ;
    RECT 0.000 56.850 28.800 57.150 ;
    LAYER MET3 ;
    RECT 0.000 57.150 28.150 57.350 ;
    LAYER MET3 ;
    RECT 0.650 57.350 28.150 57.450 ;
    LAYER MET3 ;
    RECT 0.650 57.450 28.800 57.650 ;
    LAYER MET3 ;
    RECT 0.000 57.650 28.800 57.750 ;
    LAYER MET3 ;
    RECT 0.000 57.750 28.150 58.050 ;
    LAYER MET3 ;
    RECT 0.000 58.050 28.800 58.350 ;
    LAYER MET3 ;
    RECT 0.000 58.350 28.150 58.650 ;
    LAYER MET3 ;
    RECT 0.000 58.650 28.800 58.950 ;
    LAYER MET3 ;
    RECT 0.000 58.950 28.150 59.250 ;
    LAYER MET3 ;
    RECT 0.000 59.250 28.800 59.550 ;
    LAYER MET3 ;
    RECT 0.000 59.550 28.150 59.750 ;
    LAYER MET3 ;
    RECT 0.650 59.750 28.150 59.850 ;
    LAYER MET3 ;
    RECT 0.650 59.850 28.800 60.050 ;
    LAYER MET3 ;
    RECT 0.000 60.050 28.800 60.150 ;
    LAYER MET3 ;
    RECT 0.000 60.150 28.150 60.450 ;
    LAYER MET3 ;
    RECT 0.000 60.450 28.800 60.750 ;
    LAYER MET3 ;
    RECT 0.000 60.750 28.150 61.050 ;
    LAYER MET3 ;
    RECT 0.000 61.050 28.800 61.350 ;
    LAYER MET3 ;
    RECT 0.000 61.350 28.150 61.650 ;
    LAYER MET3 ;
    RECT 0.000 61.650 28.800 61.950 ;
    LAYER MET3 ;
    RECT 0.000 61.950 28.150 62.150 ;
    LAYER MET3 ;
    RECT 0.650 62.150 28.150 62.250 ;
    LAYER MET3 ;
    RECT 0.650 62.250 28.800 62.450 ;
    LAYER MET3 ;
    RECT 0.000 62.450 28.800 62.550 ;
    LAYER MET3 ;
    RECT 0.000 62.550 28.150 62.850 ;
    LAYER MET3 ;
    RECT 0.000 62.850 28.800 63.150 ;
    LAYER MET3 ;
    RECT 0.000 63.150 28.150 63.450 ;
    LAYER MET3 ;
    RECT 0.000 63.450 28.800 63.750 ;
    LAYER MET3 ;
    RECT 0.000 63.750 28.150 64.050 ;
    LAYER MET3 ;
    RECT 0.000 64.050 28.800 64.350 ;
    LAYER MET3 ;
    RECT 0.000 64.350 28.150 64.550 ;
    LAYER MET3 ;
    RECT 0.650 64.550 28.150 64.650 ;
    LAYER MET3 ;
    RECT 0.650 64.650 28.800 64.850 ;
    LAYER MET3 ;
    RECT 0.000 64.850 28.800 64.950 ;
    LAYER MET3 ;
    RECT 0.000 64.950 28.150 65.250 ;
    LAYER MET3 ;
    RECT 0.000 65.250 28.800 65.550 ;
    LAYER MET3 ;
    RECT 0.000 65.550 28.150 65.850 ;
    LAYER MET3 ;
    RECT 0.000 65.850 28.800 66.150 ;
    LAYER MET3 ;
    RECT 0.000 66.150 28.150 66.450 ;
    LAYER MET3 ;
    RECT 0.000 66.450 28.800 66.750 ;
    LAYER MET3 ;
    RECT 0.000 66.750 28.150 66.950 ;
    LAYER MET3 ;
    RECT 0.650 66.950 28.150 67.050 ;
    LAYER MET3 ;
    RECT 0.650 67.050 28.800 67.250 ;
    LAYER MET3 ;
    RECT 0.000 67.250 28.800 67.350 ;
    LAYER MET3 ;
    RECT 0.000 67.350 28.150 67.650 ;
    LAYER MET3 ;
    RECT 0.000 67.650 28.800 67.950 ;
    LAYER MET3 ;
    RECT 0.000 67.950 28.150 68.250 ;
    LAYER MET3 ;
    RECT 0.000 68.250 28.800 68.550 ;
    LAYER MET3 ;
    RECT 0.000 68.550 28.150 68.850 ;
    LAYER MET3 ;
    RECT 0.000 68.850 28.800 69.150 ;
    LAYER MET3 ;
    RECT 0.000 69.150 28.150 69.350 ;
    LAYER MET3 ;
    RECT 0.650 69.350 28.150 69.450 ;
    LAYER MET3 ;
    RECT 0.650 69.450 28.800 69.650 ;
    LAYER MET3 ;
    RECT 0.000 69.650 28.800 69.750 ;
    LAYER MET3 ;
    RECT 0.000 69.750 28.150 70.050 ;
    LAYER MET3 ;
    RECT 0.000 70.050 28.800 70.350 ;
    LAYER MET3 ;
    RECT 0.000 70.350 28.150 70.650 ;
    LAYER MET3 ;
    RECT 0.000 70.650 28.800 70.950 ;
    LAYER MET3 ;
    RECT 0.000 70.950 28.150 71.250 ;
    LAYER MET3 ;
    RECT 0.000 71.250 28.800 71.550 ;
    LAYER MET3 ;
    RECT 0.000 71.550 28.150 71.750 ;
    LAYER MET3 ;
    RECT 0.650 71.750 28.150 71.850 ;
    LAYER MET3 ;
    RECT 0.650 71.850 28.800 72.050 ;
    LAYER MET3 ;
    RECT 0.000 72.050 28.800 72.150 ;
    LAYER MET3 ;
    RECT 0.000 72.150 28.150 72.450 ;
    LAYER MET3 ;
    RECT 0.000 72.450 28.800 72.750 ;
    LAYER MET3 ;
    RECT 0.000 72.750 28.150 73.050 ;
    LAYER MET3 ;
    RECT 0.000 73.050 28.800 73.350 ;
    LAYER MET3 ;
    RECT 0.000 73.350 28.150 73.650 ;
    LAYER MET3 ;
    RECT 0.000 73.650 28.800 73.950 ;
    LAYER MET3 ;
    RECT 0.000 73.950 28.150 74.150 ;
    LAYER MET3 ;
    RECT 0.650 74.150 28.150 74.250 ;
    LAYER MET3 ;
    RECT 0.650 74.250 28.800 74.450 ;
    LAYER MET3 ;
    RECT 0.000 74.450 28.800 74.550 ;
    LAYER MET3 ;
    RECT 0.000 74.550 28.150 74.850 ;
    LAYER MET3 ;
    RECT 0.000 74.850 28.800 75.150 ;
    LAYER MET3 ;
    RECT 0.000 75.150 28.150 75.450 ;
    LAYER MET3 ;
    RECT 0.000 75.450 28.800 75.750 ;
    LAYER MET3 ;
    RECT 0.000 75.750 28.150 76.050 ;
    LAYER MET3 ;
    RECT 0.000 76.050 28.800 76.350 ;
    LAYER MET3 ;
    RECT 0.000 76.350 28.150 76.550 ;
    LAYER MET3 ;
    RECT 0.650 76.550 28.150 76.650 ;
    LAYER MET3 ;
    RECT 0.650 76.650 28.800 76.850 ;
    LAYER MET3 ;
    RECT 0.000 76.850 28.800 76.950 ;
    LAYER MET3 ;
    RECT 0.000 76.950 28.150 77.250 ;
    LAYER MET3 ;
    RECT 0.000 77.250 28.800 77.550 ;
    LAYER MET3 ;
    RECT 0.000 77.550 28.150 77.850 ;
    LAYER MET3 ;
    RECT 0.000 77.850 28.800 78.150 ;
    LAYER MET3 ;
    RECT 0.000 78.150 28.150 78.450 ;
    LAYER MET3 ;
    RECT 0.000 78.450 28.800 78.750 ;
    LAYER MET3 ;
    RECT 0.000 78.750 28.150 78.950 ;
    LAYER MET3 ;
    RECT 0.650 78.950 28.150 79.050 ;
    LAYER MET3 ;
    RECT 0.650 79.050 28.800 79.250 ;
    LAYER MET3 ;
    RECT 0.000 79.250 28.800 79.350 ;
    LAYER MET3 ;
    RECT 0.000 79.350 28.150 79.650 ;
    LAYER MET3 ;
    RECT 0.000 79.650 28.800 79.950 ;
    LAYER MET3 ;
    RECT 0.000 79.950 28.150 80.250 ;
    LAYER MET3 ;
    RECT 0.000 80.250 28.800 84.000 ;
    LAYER MET4 ;
    RECT 0.000 0.000 4.550 84.000 ;
    LAYER MET4 ;
    RECT 4.550 0.650 4.850 83.350 ;
    LAYER MET4 ;
    RECT 4.850 0.000 5.150 84.000 ;
    LAYER MET4 ;
    RECT 5.150 0.650 5.450 83.350 ;
    LAYER MET4 ;
    RECT 5.450 0.000 5.750 84.000 ;
    LAYER MET4 ;
    RECT 5.750 0.650 6.050 83.350 ;
    LAYER MET4 ;
    RECT 6.050 0.000 6.350 84.000 ;
    LAYER MET4 ;
    RECT 6.350 0.650 6.650 83.350 ;
    LAYER MET4 ;
    RECT 6.650 0.000 6.950 84.000 ;
    LAYER MET4 ;
    RECT 6.950 0.650 7.250 83.350 ;
    LAYER MET4 ;
    RECT 7.250 0.000 7.550 84.000 ;
    LAYER MET4 ;
    RECT 7.550 0.650 7.850 83.350 ;
    LAYER MET4 ;
    RECT 7.850 0.000 8.150 84.000 ;
    LAYER MET4 ;
    RECT 8.150 0.650 8.450 83.350 ;
    LAYER MET4 ;
    RECT 8.450 0.000 8.750 84.000 ;
    LAYER MET4 ;
    RECT 8.750 0.650 9.050 83.350 ;
    LAYER MET4 ;
    RECT 9.050 0.000 9.350 84.000 ;
    LAYER MET4 ;
    RECT 9.350 0.650 9.650 83.350 ;
    LAYER MET4 ;
    RECT 9.650 0.000 9.950 84.000 ;
    LAYER MET4 ;
    RECT 9.950 0.650 10.250 83.350 ;
    LAYER MET4 ;
    RECT 10.250 0.000 12.150 84.000 ;
    LAYER MET4 ;
    RECT 12.150 0.650 12.450 83.350 ;
    LAYER MET4 ;
    RECT 12.450 0.000 12.750 84.000 ;
    LAYER MET4 ;
    RECT 12.750 0.650 13.050 83.350 ;
    LAYER MET4 ;
    RECT 13.050 0.000 13.350 84.000 ;
    LAYER MET4 ;
    RECT 13.350 0.650 13.650 83.350 ;
    LAYER MET4 ;
    RECT 13.650 0.000 13.950 84.000 ;
    LAYER MET4 ;
    RECT 13.950 0.650 14.250 83.350 ;
    LAYER MET4 ;
    RECT 14.250 0.000 14.550 84.000 ;
    LAYER MET4 ;
    RECT 14.550 0.650 14.850 83.350 ;
    LAYER MET4 ;
    RECT 14.850 0.000 15.150 84.000 ;
    LAYER MET4 ;
    RECT 15.150 0.650 15.450 83.350 ;
    LAYER MET4 ;
    RECT 15.450 0.000 15.750 84.000 ;
    LAYER MET4 ;
    RECT 15.750 0.650 16.050 83.350 ;
    LAYER MET4 ;
    RECT 16.050 0.000 16.350 84.000 ;
    LAYER MET4 ;
    RECT 16.350 0.650 16.650 83.350 ;
    LAYER MET4 ;
    RECT 16.650 0.000 16.950 84.000 ;
    LAYER MET4 ;
    RECT 16.950 0.650 17.250 83.350 ;
    LAYER MET4 ;
    RECT 17.250 0.000 17.550 84.000 ;
    LAYER MET4 ;
    RECT 17.550 0.650 17.850 83.350 ;
    LAYER MET4 ;
    RECT 17.850 0.000 18.150 84.000 ;
    LAYER MET4 ;
    RECT 18.150 0.650 18.450 83.350 ;
    LAYER MET4 ;
    RECT 18.450 0.000 18.750 84.000 ;
    LAYER MET4 ;
    RECT 18.750 0.650 19.050 83.350 ;
    LAYER MET4 ;
    RECT 19.050 0.000 20.950 84.000 ;
    LAYER MET4 ;
    RECT 20.950 0.650 21.250 83.350 ;
    LAYER MET4 ;
    RECT 21.250 0.000 21.550 84.000 ;
    LAYER MET4 ;
    RECT 21.550 0.650 21.850 83.350 ;
    LAYER MET4 ;
    RECT 21.850 0.000 22.150 84.000 ;
    LAYER MET4 ;
    RECT 22.150 0.650 22.450 83.350 ;
    LAYER MET4 ;
    RECT 22.450 0.000 22.750 84.000 ;
    LAYER MET4 ;
    RECT 22.750 0.650 23.050 83.350 ;
    LAYER MET4 ;
    RECT 23.050 0.000 23.350 84.000 ;
    LAYER MET4 ;
    RECT 23.350 0.650 23.650 83.350 ;
    LAYER MET4 ;
    RECT 23.650 0.000 23.950 84.000 ;
    LAYER MET4 ;
    RECT 23.950 0.650 24.250 83.350 ;
    LAYER MET4 ;
    RECT 24.250 0.000 28.800 84.000 ;
    LAYER MET5 ;
    RECT 0.000 0.000 28.800 2.400 ;
    LAYER MET5 ;
    RECT 0.000 3.600 28.800 10.800 ;
    LAYER MET5 ;
    RECT 0.000 12.000 28.800 19.200 ;
    LAYER MET5 ;
    RECT 0.000 20.400 28.800 27.600 ;
    LAYER MET5 ;
    RECT 0.000 28.800 28.800 36.000 ;
    LAYER MET5 ;
    RECT 0.000 37.200 28.800 44.400 ;
    LAYER MET5 ;
    RECT 0.000 45.600 28.800 52.800 ;
    LAYER MET5 ;
    RECT 0.000 54.000 28.800 61.200 ;
    LAYER MET5 ;
    RECT 0.000 62.400 28.800 69.600 ;
    LAYER MET5 ;
    RECT 0.000 70.800 28.800 78.000 ;
    LAYER MET5 ;
    RECT 0.000 79.200 28.800 84.000 ;
  END

END W_term

END LIBRARY
